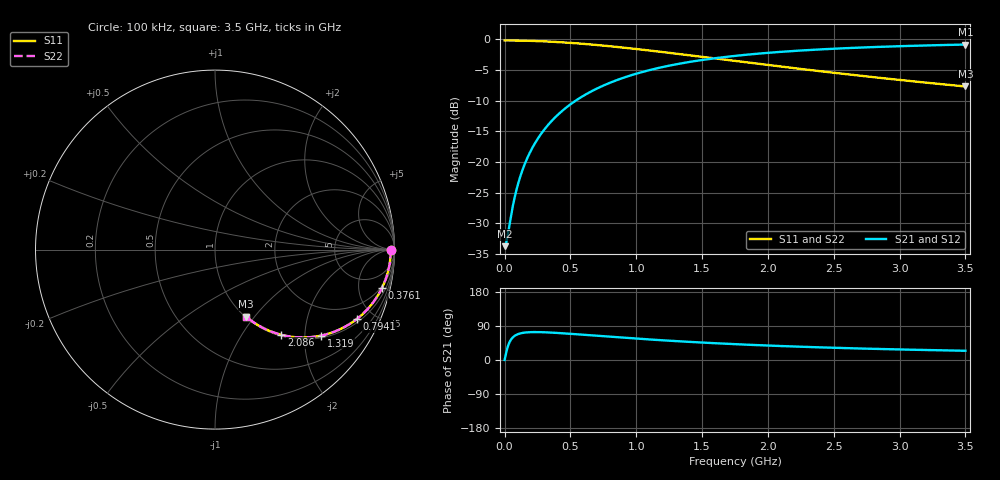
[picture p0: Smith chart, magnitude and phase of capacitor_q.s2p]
! Created Fri Jul 21 17:19:19 2023
# mhz S ri R 50
! 2 Port Network Data from SP1.SP block
! freq  reS11  imS11  reS21  imS21  reS12  imS12  reS22  imS22
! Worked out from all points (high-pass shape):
!   7001 points, 100 kHz to 3.5 GHz, reference 50 ohm
!   highest |S21| = -0.85 dB at 3.5 GHz (marker M1); lowest = -33.8 dB at 100 kHz (marker M2)
!   |S21| within 3 dB of the highest: 1.36 GHz to end of sweep
!   lowest |S11| = -7.7 dB at 3.5 GHz (marker M3), VSWR 2.40, Z = 50.4 - j45.5 ohm
!   |S11| at or under -10 dB: nowhere
!   |S22| runs from -7.7 to -0.2 dB; largest |S21 - S12| = 1.4e-15
!   S11 on the Smith chart (normalised r, x): 100 kHz: 96, -0; 376.1 MHz: 1.74, -8.40; 794.1 MHz: 1.17, -4.00; 1.319 GHz: 1.06, -2.41; 2.086 GHz: 1.02, -1.53; 3.5 GHz: 1.01, -0.91
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0.1  0.9795 -6.03e-05  0.0205 6.03e-05  0.0205 6.03e-05  0.9795 -6.03e-05
10.1  0.9794 -0.00609  0.0206 0.00609  0.0206 0.00609  0.9794 -0.00609
19.6  0.9793 -0.0118  0.0207 0.0118  0.0207 0.0118  0.9793 -0.0118
60.6  0.9781 -0.0365  0.0219 0.0365  0.0219 0.0365  0.9781 -0.0365
87.6  0.9766 -0.0527  0.0234 0.0527  0.0234 0.0527  0.9766 -0.0527
116.6  0.9745 -0.0699  0.0255 0.0699  0.0255 0.0699  0.9745 -0.0699
149.6  0.9713 -0.0894  0.0287 0.0894  0.0287 0.0894  0.9713 -0.0894
194.6  0.9656 -0.1156  0.0344 0.1156  0.0344 0.1156  0.9656 -0.1156
247.1  0.9573 -0.1456  0.0427 0.1456  0.0427 0.1456  0.9573 -0.1456
307.6  0.9456 -0.179  0.0544 0.179  0.0544 0.179  0.9456 -0.179
376.1  0.9297 -0.2152  0.0703 0.2152  0.0703 0.2152  0.9297 -0.2152
472.6  0.9031 -0.2627  0.0969 0.2627  0.0969 0.2627  0.9031 -0.2627
583.6  0.8676 -0.3116  0.1324 0.3116  0.1324 0.3116  0.8676 -0.3116
794.1  0.7906 -0.3864  0.2094 0.3864  0.2094 0.3864  0.7906 -0.3864
968.6  0.7227 -0.4308  0.2773 0.4308  0.2773 0.4308  0.7227 -0.4308
1167.1  0.6461 -0.4641  0.3539 0.4641  0.3539 0.4641  0.6461 -0.4641
1319.1  0.5904 -0.4793  0.4096 0.4793  0.4096 0.4793  0.5904 -0.4793
1750.1  0.4535 -0.4884  0.5465 0.4884  0.5465 0.4884  0.4535 -0.4884
2086.1  0.3699 -0.4748  0.6301 0.4748  0.6301 0.4748  0.3699 -0.4748
2333.6  0.3198 -0.4593  0.6802 0.4593  0.6802 0.4593  0.3198 -0.4593
2917.1  0.2319 -0.4164  0.7681 0.4164  0.7681 0.4164  0.2319 -0.4164
3500  0.1737 -0.3741  0.8263 0.3741  0.8263 0.3741  0.1737 -0.3741
